VERSION 5.8 ;
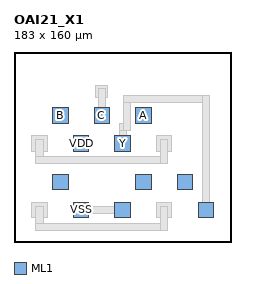
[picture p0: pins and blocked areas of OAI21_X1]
MACRO OAI21_X1
  CLASS CORE ;
  ORIGIN 0 0 ;
  SIZE 183 BY 160 ;
  PIN A
    DIRECTION INPUT ;
    USE SIGNAL ;
    PORT
      LAYER ML1 ;
        RECT 102.5 100 115.5 113 ;
        RECT 102.5 44 115.5 57 ;
    END
  END A
  PIN B
    DIRECTION INPUT ;
    USE SIGNAL ;
    PORT
      LAYER ML1 ;
        RECT 32.5 100 45.5 113 ;
        RECT 32.5 44 45.5 57 ;
    END
  END B
  PIN C
    DIRECTION INPUT ;
    USE SIGNAL ;
    PORT
      LAYER ML1 ;
        RECT 67.5 100 80.5 113 ;
        RECT 137.5 44 150.5 57 ;
    END
  END C
  PIN Y
    DIRECTION OUTPUT ;
    USE SIGNAL ;
    PORT
      LAYER ML1 ;
        RECT 85 76.5 98 89.5 ;
        RECT 155 20.5 168 33.5 ;
    END
  END Y
  PIN VDD
    DIRECTION INOUT ;
    USE POWER ;
    PORT
      LAYER ML1 ;
        RECT 50 76.5 63 89.5 ;
    END
  END VDD
  PIN VSS
    DIRECTION INOUT ;
    USE GROUND ;
    PORT
      LAYER ML1 ;
        RECT 50 20.5 63 33.5 ;
        RECT 85 20.5 98 33.5 ;
    END
  END VSS
  OBS
    LAYER ML1 ;
      RECT 15 20.5 28 33.5 ;
      RECT 15 76.5 28 89.5 ;
      RECT 18.5 10 24.5 30 ;
      RECT 18.5 10 129.5 16 ;
      RECT 18.5 66 24.5 86 ;
      RECT 18.5 66 129.5 72 ;
      RECT 53.5 24 94.5 30 ;
      RECT 69 121.5 79 131.5 ;
      RECT 71 103.5 77 129.5 ;
      RECT 88.5 80 94.5 100 ;
      RECT 88.5 94 98 100 ;
      RECT 92 94 98 123.5 ;
      RECT 92 117.5 164.5 123.5 ;
      RECT 120 20.5 133 33.5 ;
      RECT 120 76.5 133 89.5 ;
      RECT 123.5 10 129.5 30 ;
      RECT 123.5 66 129.5 86 ;
      RECT 158.5 24 164.5 123.5 ;
  END
END OAI21_X1
